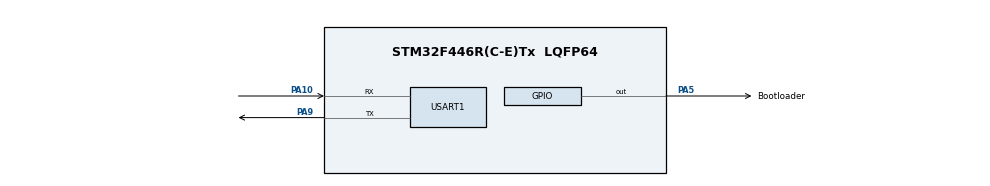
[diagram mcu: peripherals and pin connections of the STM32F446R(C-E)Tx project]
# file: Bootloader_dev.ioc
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Mcu.Family=STM32F4
Mcu.Name=STM32F446R(C-E)Tx
Mcu.Package=LQFP64
NVIC.PriorityGroup=NVIC_PRIORITYGROUP_0
PA10.Mode=Asynchronous
PA10.Signal=USART1_RX
PA13.Mode=Serial_Wire
PA13.Signal=SYS_JTMS-SWDIO
PA14.Mode=Serial_Wire
PA14.Signal=SYS_JTCK-SWCLK
PA5.GPIO_Label=Bootloader
PA5.Signal=GPIO_Output
PA9.Mode=Asynchronous
PA9.Signal=USART1_TX
ProjectManager.HeapSize=0x200
ProjectManager.StackSize=0x400
ProjectManager.TargetToolchain=STM32CubeIDE
RCC.AHBFreq_Value=50000000
RCC.APB1CLKDivider=RCC_HCLK_DIV2
RCC.APB1Freq_Value=25000000
RCC.APB1TimFreq_Value=50000000
RCC.APB2Freq_Value=50000000
RCC.APB2TimFreq_Value=50000000
RCC.CortexFreq_Value=50000000
RCC.HCLKFreq_Value=50000000
RCC.PLLM=8
RCC.PLLN=50
RCC.SYSCLKFreq_VALUE=50000000
RCC.SYSCLKSource=RCC_SYSCLKSOURCE_PLLCLK
RCC.USBFreq_Value=50000000
RCC.VCOOutputFreq_Value=100000000
USART1.VirtualMode=VM_ASYNC
board=NUCLEO-F446RE

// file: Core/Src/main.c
/* USER CODE BEGIN Header */
/**
  ******************************************************************************
  * @file           : main.c
  * @brief          : Main program body
  ******************************************************************************
  * @attention
  *
  * Copyright (c) 2025 STMicroelectronics.
  * All rights reserved.
  *
  * This software is licensed under terms that can be found in the LICENSE file
  * in the root directory of this software component.
  * If no LICENSE file comes with this software, it is provided AS-IS.
  *
  ******************************************************************************
  */
/* USER CODE END Header */
#include "main.h"

/* USER CODE BEGIN Includes */
#include "bl_jump.h"
/* USER CODE END Includes */

UART_HandleTypeDef huart1;

void SystemClock_Config(void);
static void MX_GPIO_Init(void);
static void MX_USART1_UART_Init(void);

int main(void)
{

  /* MCU Configuration--------------------------------------------------------*/

  /* Reset of all peripherals, Initializes the Flash interface and the Systick. */
  HAL_Init();

  /* Configure the system clock */
  SystemClock_Config();

  /* Initialize all configured peripherals */
  MX_GPIO_Init();
  MX_USART1_UART_Init();
  /* USER CODE BEGIN 2 */

  HAL_Delay(100);

  HAL_UART_Transmit(&huart1, (uint8_t *)"Inside Bootloader!!\r\n", 21, 100);

  jumpToApplication();

  /* USER CODE END 2 */

  /* Infinite loop */
  while (1)
  {

    /* USER CODE BEGIN 3 */

	  HAL_GPIO_TogglePin(Bootloader_GPIO_Port,Bootloader_Pin);
	  HAL_Delay(100);
  }
  /* USER CODE END 3 */
}

void SystemClock_Config(void)
{
  RCC_OscInitTypeDef RCC_OscInitStruct = {0};
  RCC_ClkInitTypeDef RCC_ClkInitStruct = {0};

  /** Initializes the RCC Oscillators according to the specified parameters
  * in the RCC_OscInitTypeDef structure.
  */
  RCC_OscInitStruct.OscillatorType = RCC_OSCILLATORTYPE_HSI;
  RCC_OscInitStruct.HSIState = RCC_HSI_ON;
  RCC_OscInitStruct.HSICalibrationValue = RCC_HSICALIBRATION_DEFAULT;
  RCC_OscInitStruct.PLL.PLLState = RCC_PLL_NONE;
  if (HAL_RCC_OscConfig(&RCC_OscInitStruct) != HAL_OK)
  {
    Error_Handler();
  }

  /** Initializes the CPU, AHB and APB buses clocks
  */
  RCC_ClkInitStruct.ClockType = RCC_CLOCKTYPE_HCLK|RCC_CLOCKTYPE_SYSCLK
                              |RCC_CLOCKTYPE_PCLK1|RCC_CLOCKTYPE_PCLK2;
  RCC_ClkInitStruct.SYSCLKSource = RCC_SYSCLKSOURCE_HSI;
  RCC_ClkInitStruct.AHBCLKDivider = RCC_SYSCLK_DIV1;
  RCC_ClkInitStruct.APB1CLKDivider = RCC_HCLK_DIV1;
  RCC_ClkInitStruct.APB2CLKDivider = RCC_HCLK_DIV1;

  if (HAL_RCC_ClockConfig(&RCC_ClkInitStruct, FLASH_LATENCY_0) != HAL_OK)
  {
    Error_Handler();
  }
}

static void MX_USART1_UART_Init(void)
{

  huart1.Instance = USART1;
  huart1.Init.BaudRate = 115200;
  huart1.Init.WordLength = UART_WORDLENGTH_8B;
  huart1.Init.StopBits = UART_STOPBITS_1;
  huart1.Init.Parity = UART_PARITY_NONE;
  huart1.Init.Mode = UART_MODE_TX_RX;
  huart1.Init.HwFlowCtl = UART_HWCONTROL_NONE;
  huart1.Init.OverSampling = UART_OVERSAMPLING_16;
  if (HAL_UART_Init(&huart1) != HAL_OK)
  {
    Error_Handler();
  }

}

static void MX_GPIO_Init(void)
{
  GPIO_InitTypeDef GPIO_InitStruct = {0};

  /* GPIO Ports Clock Enable */
  __HAL_RCC_GPIOA_CLK_ENABLE();

  /*Configure GPIO pin Output Level */
  HAL_GPIO_WritePin(GPIOA, GPIO_PIN_4, GPIO_PIN_RESET);

  /*Configure GPIO pin : PA4 */
  GPIO_InitStruct.Pin = GPIO_PIN_4;
  GPIO_InitStruct.Mode = GPIO_MODE_OUTPUT_PP;
  GPIO_InitStruct.Pull = GPIO_NOPULL;
  GPIO_InitStruct.Speed = GPIO_SPEED_FREQ_LOW;
  HAL_GPIO_Init(GPIOA, &GPIO_InitStruct);

}

void Error_Handler(void)
{
  __disable_irq();
  while (1)
  {
  }
}
